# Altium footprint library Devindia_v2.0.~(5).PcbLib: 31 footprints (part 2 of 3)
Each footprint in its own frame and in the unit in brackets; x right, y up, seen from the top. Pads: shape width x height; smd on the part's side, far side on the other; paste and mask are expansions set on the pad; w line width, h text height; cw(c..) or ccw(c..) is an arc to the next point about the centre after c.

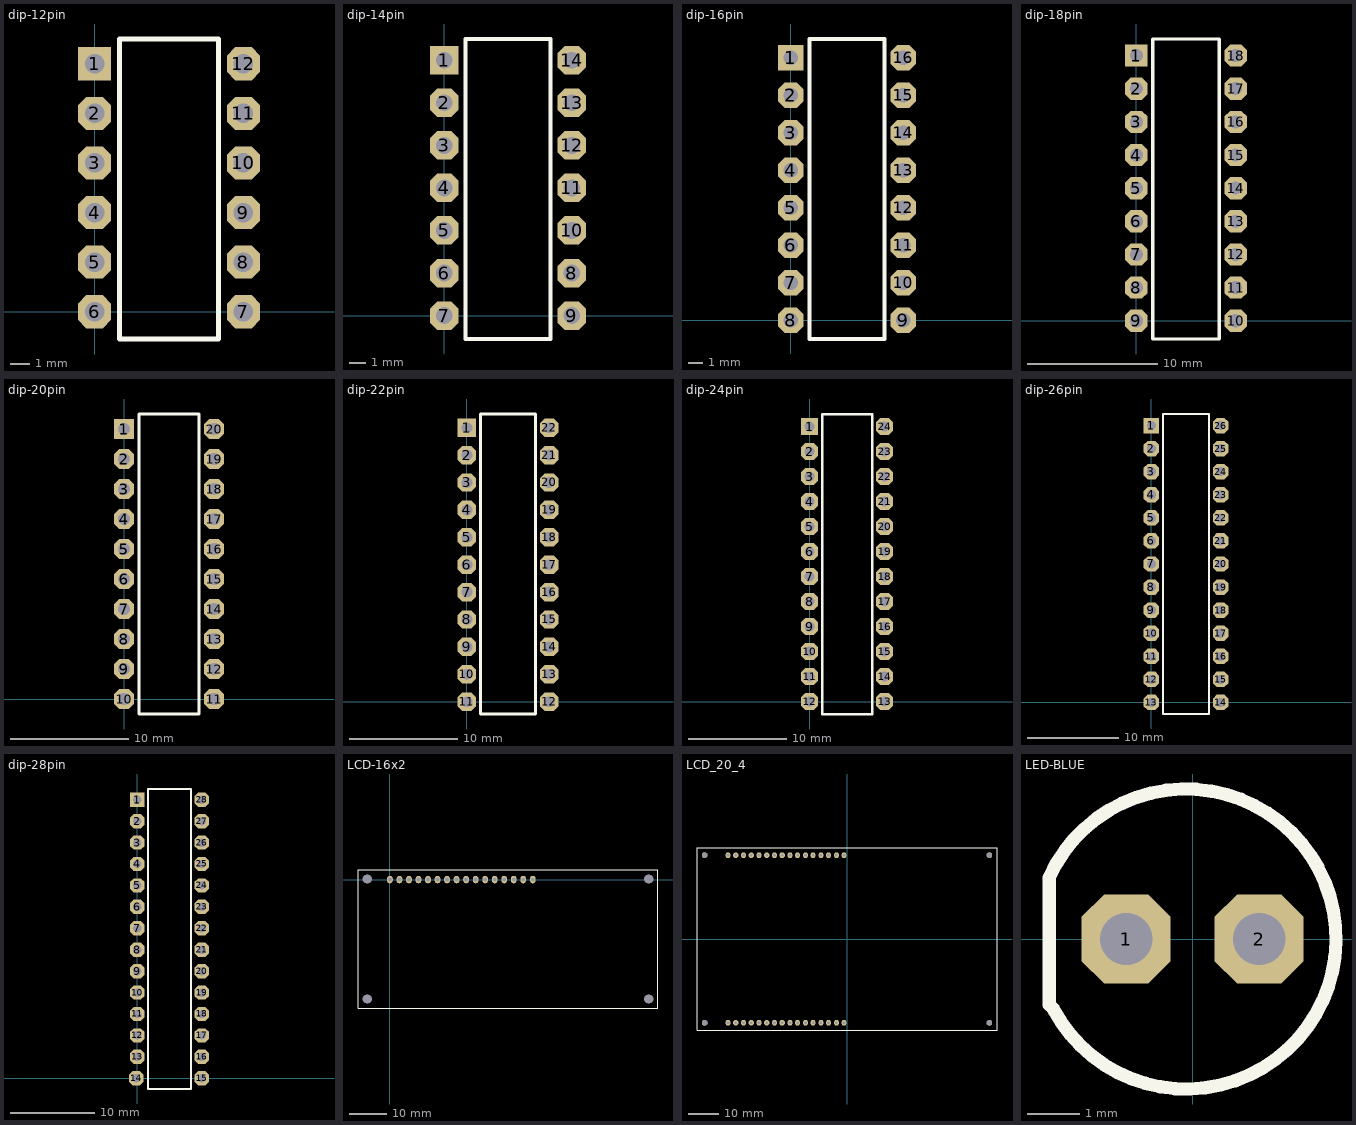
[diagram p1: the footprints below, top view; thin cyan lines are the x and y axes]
## dip-12pin [mm]
pads (12):
  rect 1.7x1.7 hole 1: 1(0,12.7)
  oct 1.7x1.7 hole 1: 2(0,10.16) 3(0,7.62) 4(0,5.08) 5(0,2.54) 6(0,0) 7(7.62,0) 8(7.62,2.54) 9(7.62,5.08) 10(7.62,7.62) 11(7.62,10.16) 12(7.62,12.7)
Top Overlay:
  lines w0.254: 1.27,-1.397 1.27,13.97 6.35,13.97 6.35,-1.397 1.27,-1.397
3D body: height 1.5, standoff 0, extent 7.493,4.699 7.747,5.461
3D body: height 1.63, standoff 1.37, extent 7.494,4.699 7.746,5.461
3D body: height 1.63, standoff 1.37, extent 5.842,4.699 7.747,5.461
3D body: height 2.5, standoff 2, extent 1.778,-1.27 5.842,13.97
3D body: height 2.51, standoff 2.5, extent 2.041,12.212 3.039,13.208
3D body: height 2, standoff 1.1, extent 1.27,-1.397 6.35,13.97
3D body: height 1.5, standoff 0, extent 7.493,12.319 7.747,13.081
3D body: height 1.63, standoff 1.37, extent 7.494,12.319 7.746,13.081
3D body: height 1.5, standoff 0, extent 7.493,9.779 7.747,10.541
3D body: height 1.63, standoff 1.37, extent 7.494,9.779 7.746,10.541
3D body: height 1.5, standoff 0, extent 7.493,7.239 7.747,8.001
3D body: height 1.63, standoff 1.37, extent 7.494,7.239 7.746,8.001
3D body: height 1.5, standoff 0, extent 7.493,2.159 7.747,2.921
3D body: height 1.63, standoff 1.37, extent 7.494,2.159 7.746,2.921
3D body: height 1.5, standoff 0, extent 7.493,-0.381 7.747,0.381
3D body: height 1.63, standoff 1.37, extent 7.494,-0.381 7.746,0.381
3D body: height 1.5, standoff 0, extent -0.127,-0.381 0.127,0.381
3D body: height 1.63, standoff 1.37, extent -0.126,-0.381 0.126,0.381
3D body: height 1.5, standoff 0, extent -0.127,2.159 0.127,2.921
3D body: height 1.63, standoff 1.37, extent -0.126,2.159 0.126,2.921
3D body: height 1.5, standoff 0, extent -0.127,4.699 0.127,5.461
3D body: height 1.63, standoff 1.37, extent -0.126,4.699 0.126,5.461
3D body: height 1.5, standoff 0, extent -0.127,7.239 0.127,8.001
3D body: height 1.63, standoff 1.37, extent -0.126,7.239 0.126,8.001
3D body: height 1.5, standoff 0, extent -0.127,9.779 0.127,10.541
3D body: height 1.63, standoff 1.37, extent -0.126,9.779 0.126,10.541
3D body: height 1.5, standoff 0, extent -0.127,12.319 0.127,13.081
3D body: height 1.63, standoff 1.37, extent -0.126,12.319 0.126,13.081
3D body: height 1.63, standoff 1.37, extent 5.842,12.319 7.747,13.081
3D body: height 1.63, standoff 1.37, extent 5.842,9.779 7.747,10.541
3D body: height 1.63, standoff 1.37, extent 5.842,7.239 7.747,8.001
3D body: height 1.63, standoff 1.37, extent 5.842,2.159 7.747,2.921
3D body: height 1.63, standoff 1.37, extent 5.842,-0.381 7.747,0.381
3D body: height 1.63, standoff 1.37, extent -0.127,-0.381 1.778,0.381
3D body: height 1.63, standoff 1.37, extent -0.127,2.159 1.778,2.921
3D body: height 1.63, standoff 1.37, extent -0.127,4.699 1.778,5.461
3D body: height 1.63, standoff 1.37, extent -0.127,7.239 1.778,8.001
3D body: height 1.63, standoff 1.37, extent -0.127,12.319 1.778,13.081
3D body: height 1.63, standoff 1.37, extent -0.127,9.779 1.778,10.541

## dip-14pin [mm]
pads (14):
  rect 1.7x1.7 hole 1: 1(0,15.24)
  oct 1.7x1.7 hole 1: 2(0,12.7) 3(0,10.16) 4(0,7.62) 5(0,5.08) 6(0,2.54) 7(0,0) 8(7.62,2.54) 9(7.62,0) 10(7.62,5.08) 11(7.62,7.62) 12(7.62,10.16) 13(7.62,12.7) 14(7.62,15.24)
Top Overlay:
  lines w0.254: 1.27,-1.397 6.35,-1.397 6.35,16.51 1.27,16.51 1.27,-1.397
3D body: height 1.5, standoff 0, extent 7.493,2.159 7.747,2.921
3D body: height 1.63, standoff 1.37, extent 7.494,2.159 7.746,2.921
3D body: height 1.63, standoff 1.37, extent 5.842,2.159 7.747,2.921
3D body: height 1.63, standoff 1.37, extent 7.621,14.859 7.873,15.621
3D body: height 1.5, standoff 0, extent 7.62,14.859 7.874,15.621
3D body: height 1.63, standoff 1.37, extent 5.842,14.859 7.747,15.621
3D body: height 1.63, standoff 1.37, extent 5.842,12.319 7.747,13.081
3D body: height 1.5, standoff 0, extent 7.62,12.319 7.874,13.081
3D body: height 1.63, standoff 1.37, extent 7.621,12.319 7.873,13.081
3D body: height 1.63, standoff 1.37, extent -0.127,12.319 1.778,13.081
3D body: height 1.63, standoff 1.37, extent -0.127,14.859 1.778,15.621
3D body: height 1.63, standoff 1.37, extent -0.127,9.779 1.778,10.541
3D body: height 1.63, standoff 1.37, extent -0.127,7.239 1.778,8.001
3D body: height 1.63, standoff 1.37, extent -0.127,4.699 1.778,5.461
3D body: height 1.63, standoff 1.37, extent -0.127,2.159 1.778,2.921
3D body: height 1.63, standoff 1.37, extent -0.127,-0.381 1.778,0.381
3D body: height 1.63, standoff 1.37, extent 5.842,-0.381 7.747,0.381
3D body: height 1.63, standoff 1.37, extent 5.842,4.699 7.747,5.461
3D body: height 1.63, standoff 1.37, extent 5.842,7.239 7.747,8.001
3D body: height 1.63, standoff 1.37, extent 5.842,9.779 7.747,10.541
3D body: height 1.63, standoff 1.37, extent -0.126,14.859 0.126,15.621
3D body: height 1.5, standoff 0, extent -0.127,14.859 0.127,15.621
3D body: height 1.63, standoff 1.37, extent -0.126,12.319 0.126,13.081
3D body: height 1.5, standoff 0, extent -0.127,12.319 0.127,13.081
3D body: height 1.63, standoff 1.37, extent -0.126,9.779 0.126,10.541
3D body: height 1.5, standoff 0, extent -0.127,9.779 0.127,10.541
3D body: height 1.63, standoff 1.37, extent -0.126,7.239 0.126,8.001
3D body: height 1.5, standoff 0, extent -0.127,7.239 0.127,8.001
3D body: height 1.63, standoff 1.37, extent -0.126,4.699 0.126,5.461
3D body: height 1.5, standoff 0, extent -0.127,4.699 0.127,5.461
3D body: height 1.63, standoff 1.37, extent -0.126,2.159 0.126,2.921
3D body: height 1.5, standoff 0, extent -0.127,2.159 0.127,2.921
3D body: height 1.63, standoff 1.37, extent -0.126,-0.381 0.126,0.381
3D body: height 1.5, standoff 0, extent -0.127,-0.381 0.127,0.381
3D body: height 1.63, standoff 1.37, extent 7.494,-0.381 7.746,0.381
3D body: height 1.5, standoff 0, extent 7.493,-0.381 7.747,0.381
3D body: height 1.63, standoff 1.37, extent 7.494,4.699 7.746,5.461
3D body: height 1.5, standoff 0, extent 7.493,4.699 7.747,5.461
3D body: height 1.63, standoff 1.37, extent 7.494,7.239 7.746,8.001
3D body: height 1.5, standoff 0, extent 7.493,7.239 7.747,8.001
3D body: height 1.63, standoff 1.37, extent 7.494,9.779 7.746,10.541
3D body: height 1.5, standoff 0, extent 7.493,9.779 7.747,10.541
3D body: height 2, standoff 1.1, extent 1.27,-1.27 6.35,16.51
3D body: height 2.51, standoff 2.5, extent 2.041,14.752 3.039,15.748
3D body: height 2.5, standoff 2, extent 1.778,-1.397 5.842,16.51

## dip-16pin [mm]
pads (16):
  rect 1.7x1.7 hole 1: 1(0,17.78)
  oct 1.7x1.7 hole 1: 2(0,15.24) 3(0,12.7) 4(0,10.16) 5(0,7.62) 6(0,5.08) 7(0,2.54) 8(0,0) 9(7.62,0) 10(7.62,2.54) 11(7.62,5.08) 12(7.62,7.62) 13(7.62,10.16) 14(7.62,12.7) 15(7.62,15.24) 16(7.62,17.78)
Top Overlay:
  lines w0.254: 1.27,-1.27 1.27,19.05 6.35,19.05 6.35,-1.27 1.27,-1.27
3D body: height 1.63, standoff 1.37, extent 7.621,12.319 7.873,13.081
3D body: height 1.5, standoff 0, extent 7.62,12.319 7.874,13.081
3D body: height 1.63, standoff 1.37, extent 5.842,12.319 7.747,13.081
3D body: height 2.5, standoff 2, extent 1.778,-1.27 5.842,19.05
3D body: height 2.51, standoff 2.5, extent 2.041,17.292 3.039,18.288
3D body: height 1.5, standoff 0, extent 7.493,17.399 7.747,18.161
3D body: height 1.63, standoff 1.37, extent 7.494,17.399 7.746,18.161
3D body: height 2, standoff 1.1, extent 1.27,-1.27 6.35,19.05
3D body: height 1.5, standoff 0, extent 7.493,7.239 7.747,8.001
3D body: height 1.63, standoff 1.37, extent 7.494,7.239 7.746,8.001
3D body: height 1.5, standoff 0, extent 7.493,4.699 7.747,5.461
3D body: height 1.63, standoff 1.37, extent 7.494,4.699 7.746,5.461
3D body: height 1.5, standoff 0, extent 7.493,2.159 7.747,2.921
3D body: height 1.63, standoff 1.37, extent 7.494,2.159 7.746,2.921
3D body: height 1.5, standoff 0, extent 7.493,-0.381 7.747,0.381
3D body: height 1.63, standoff 1.37, extent 7.494,-0.381 7.746,0.381
3D body: height 1.5, standoff 0, extent -0.127,-0.381 0.127,0.381
3D body: height 1.63, standoff 1.37, extent -0.126,-0.381 0.126,0.381
3D body: height 1.5, standoff 0, extent -0.127,2.159 0.127,2.921
3D body: height 1.63, standoff 1.37, extent -0.126,2.159 0.126,2.921
3D body: height 1.5, standoff 0, extent -0.127,4.699 0.127,5.461
3D body: height 1.63, standoff 1.37, extent -0.126,4.699 0.126,5.461
3D body: height 1.5, standoff 0, extent -0.127,7.239 0.127,8.001
3D body: height 1.63, standoff 1.37, extent -0.126,7.239 0.126,8.001
3D body: height 1.5, standoff 0, extent -0.127,9.779 0.127,10.541
3D body: height 1.63, standoff 1.37, extent -0.126,9.779 0.126,10.541
3D body: height 1.5, standoff 0, extent -0.127,12.319 0.127,13.081
3D body: height 1.63, standoff 1.37, extent -0.126,12.319 0.126,13.081
3D body: height 1.5, standoff 0, extent -0.127,14.859 0.127,15.621
3D body: height 1.63, standoff 1.37, extent -0.126,14.859 0.126,15.621
3D body: height 1.5, standoff 0, extent -0.127,17.399 0.127,18.161
3D body: height 1.63, standoff 1.37, extent -0.126,17.399 0.126,18.161
3D body: height 1.63, standoff 1.37, extent 5.842,7.239 7.747,8.001
3D body: height 1.63, standoff 1.37, extent 5.842,4.699 7.747,5.461
3D body: height 1.63, standoff 1.37, extent 5.842,2.159 7.747,2.921
3D body: height 1.63, standoff 1.37, extent 5.842,-0.381 7.747,0.381
3D body: height 1.63, standoff 1.37, extent -0.127,-0.381 1.778,0.381
3D body: height 1.63, standoff 1.37, extent -0.127,2.159 1.778,2.921
3D body: height 1.63, standoff 1.37, extent -0.127,4.699 1.778,5.461
3D body: height 1.63, standoff 1.37, extent -0.127,7.239 1.778,8.001
3D body: height 1.63, standoff 1.37, extent -0.127,9.779 1.778,10.541
3D body: height 1.63, standoff 1.37, extent -0.127,12.319 1.778,13.081
3D body: height 1.63, standoff 1.37, extent -0.127,17.399 1.778,18.161
3D body: height 1.63, standoff 1.37, extent -0.127,14.859 1.778,15.621
3D body: height 1.63, standoff 1.37, extent 7.621,9.779 7.873,10.541
3D body: height 1.5, standoff 0, extent 7.62,9.779 7.874,10.541
3D body: height 1.63, standoff 1.37, extent 5.842,9.779 7.747,10.541
3D body: height 1.63, standoff 1.37, extent 5.842,14.859 7.747,15.621
3D body: height 1.63, standoff 1.37, extent 5.842,17.399 7.747,18.161
3D body: height 1.5, standoff 0, extent 7.62,17.399 7.874,18.161
3D body: height 1.63, standoff 1.37, extent 7.621,17.399 7.873,18.161
3D body: height 1.5, standoff 0, extent 7.62,14.859 7.874,15.621
3D body: height 1.63, standoff 1.37, extent 7.621,14.859 7.873,15.621

## dip-18pin [mm]
pads (18):
  rect 1.7x1.7 hole 1: 1(0,20.32)
  oct 1.7x1.7 hole 1: 2(0,17.78) 3(0,15.24) 4(0,12.7) 5(0,10.16) 6(0,7.62) 7(0,5.08) 8(0,2.54) 9(0,0) 10(7.62,0) 11(7.62,2.54) 12(7.62,5.08) 13(7.62,7.62) 14(7.62,10.16) 15(7.62,12.7) 16(7.62,15.24) 17(7.62,17.78) 18(7.62,20.32)
Top Overlay:
  lines w0.254: 1.27,-1.397 6.35,-1.397 6.35,21.59 1.27,21.59 1.27,-1.397
3D body: height 1.63, standoff 1.37, extent 7.621,12.319 7.873,13.081
3D body: height 1.5, standoff 0, extent 7.62,12.319 7.874,13.081
3D body: height 1.63, standoff 1.37, extent 7.621,14.859 7.873,15.621
3D body: height 1.5, standoff 0, extent 7.62,14.859 7.874,15.621
3D body: height 1.63, standoff 1.37, extent 5.842,19.939 7.747,20.701
3D body: height 1.63, standoff 1.37, extent 5.842,17.399 7.747,18.161
3D body: height 1.63, standoff 1.37, extent 7.621,19.939 7.873,20.701
3D body: height 1.5, standoff 0, extent 7.62,19.939 7.874,20.701
3D body: height 1.63, standoff 1.37, extent 5.842,14.859 7.747,15.621
3D body: height 1.63, standoff 1.37, extent 7.621,17.399 7.873,18.161
3D body: height 1.5, standoff 0, extent 7.62,17.399 7.874,18.161
3D body: height 1.63, standoff 1.37, extent 5.842,12.319 7.747,13.081
3D body: height 1.63, standoff 1.37, extent 5.842,7.239 7.747,8.001
3D body: height 1.5, standoff 0, extent 7.62,7.239 7.874,8.001
3D body: height 1.63, standoff 1.37, extent 7.621,7.239 7.873,8.001
3D body: height 1.63, standoff 1.37, extent -0.127,17.399 1.778,18.161
3D body: height 1.63, standoff 1.37, extent -0.127,19.939 1.778,20.701
3D body: height 1.63, standoff 1.37, extent -0.127,14.859 1.778,15.621
3D body: height 1.63, standoff 1.37, extent -0.127,12.319 1.778,13.081
3D body: height 1.63, standoff 1.37, extent -0.127,9.779 1.778,10.541
3D body: height 1.63, standoff 1.37, extent -0.127,7.239 1.778,8.001
3D body: height 1.63, standoff 1.37, extent -0.127,4.699 1.778,5.461
3D body: height 1.63, standoff 1.37, extent -0.127,2.159 1.778,2.921
3D body: height 1.63, standoff 1.37, extent 5.842,-0.381 7.747,0.381
3D body: height 1.63, standoff 1.37, extent 5.842,2.159 7.747,2.921
3D body: height 1.63, standoff 1.37, extent 5.842,4.699 7.747,5.461
3D body: height 1.63, standoff 1.37, extent -0.126,19.939 0.126,20.701
3D body: height 1.5, standoff 0, extent -0.127,19.939 0.127,20.701
3D body: height 1.63, standoff 1.37, extent -0.126,17.399 0.126,18.161
3D body: height 1.5, standoff 0, extent -0.127,17.399 0.127,18.161
3D body: height 1.63, standoff 1.37, extent -0.126,14.859 0.126,15.621
3D body: height 1.5, standoff 0, extent -0.127,14.859 0.127,15.621
3D body: height 1.63, standoff 1.37, extent -0.126,12.319 0.126,13.081
3D body: height 1.5, standoff 0, extent -0.127,12.319 0.127,13.081
3D body: height 1.63, standoff 1.37, extent -0.126,9.779 0.126,10.541
3D body: height 1.5, standoff 0, extent -0.127,9.779 0.127,10.541
3D body: height 1.63, standoff 1.37, extent -0.126,7.239 0.126,8.001
3D body: height 1.5, standoff 0, extent -0.127,7.239 0.127,8.001
3D body: height 1.63, standoff 1.37, extent -0.126,4.699 0.126,5.461
3D body: height 1.5, standoff 0, extent -0.127,4.699 0.127,5.461
3D body: height 1.63, standoff 1.37, extent -0.126,2.159 0.126,2.921
3D body: height 1.5, standoff 0, extent -0.127,2.159 0.127,2.921
3D body: height 1.63, standoff 1.37, extent 7.494,-0.381 7.746,0.381
3D body: height 1.5, standoff 0, extent 7.493,-0.381 7.747,0.381
3D body: height 1.63, standoff 1.37, extent 7.494,2.159 7.746,2.921
3D body: height 1.5, standoff 0, extent 7.493,2.159 7.747,2.921
3D body: height 1.63, standoff 1.37, extent 7.494,4.699 7.746,5.461
3D body: height 1.5, standoff 0, extent 7.493,4.699 7.747,5.461
3D body: height 2, standoff 1.1, extent 1.27,-1.397 6.35,21.59
3D body: height 1.63, standoff 1.37, extent 7.494,14.859 7.746,15.621
3D body: height 1.5, standoff 0, extent 7.493,14.859 7.747,15.621
3D body: height 2.51, standoff 2.5, extent 2.041,19.832 3.039,20.828
3D body: height 2.5, standoff 2, extent 1.778,-1.397 5.842,21.59
3D body: height 1.63, standoff 1.37, extent -0.127,-0.381 1.778,0.381
3D body: height 1.63, standoff 1.37, extent -0.126,-0.381 0.126,0.381
3D body: height 1.5, standoff 0, extent -0.127,-0.381 0.127,0.381
3D body: height 1.63, standoff 1.37, extent 5.842,9.779 7.747,10.541
3D body: height 1.63, standoff 1.37, extent 7.494,9.779 7.746,10.541
3D body: height 1.5, standoff 0, extent 7.493,9.779 7.747,10.541

## dip-20pin [mm]
pads (20):
  rect 1.7x1.7 hole 1: 1(0,22.86)
  oct 1.7x1.7 hole 1: 2(0,20.32) 3(0,17.78) 4(0,15.24) 5(0,12.7) 6(0,10.16) 7(0,7.62) 8(0,5.08) 9(0,2.54) 10(0,0) 11(7.62,0) 12(7.62,2.54) 13(7.62,5.08) 14(7.62,7.62) 15(7.62,10.16) 16(7.62,12.7) 17(7.62,15.24) 18(7.62,17.78) 19(7.62,20.32) 20(7.62,22.86)
Top Overlay:
  lines w0.254: 1.27,-1.27 6.35,-1.27 6.35,24.13 1.27,24.13 1.27,-1.27
3D body: height 1.5, standoff 0, extent -0.127,4.699 0.127,5.461
3D body: height 1.63, standoff 1.37, extent -0.126,4.699 0.126,5.461
3D body: height 1.63, standoff 1.37, extent -0.127,4.699 1.778,5.461
3D body: height 1.5, standoff 0, extent 7.493,7.239 7.747,8.001
3D body: height 1.63, standoff 1.37, extent 7.494,7.239 7.746,8.001
3D body: height 1.63, standoff 1.37, extent 5.842,7.239 7.747,8.001
3D body: height 1.5, standoff 0, extent -0.127,2.159 0.127,2.921
3D body: height 1.63, standoff 1.37, extent -0.126,2.159 0.126,2.921
3D body: height 1.63, standoff 1.37, extent -0.127,2.159 1.778,2.921
3D body: height 1.63, standoff 1.37, extent 7.621,9.779 7.873,10.541
3D body: height 1.5, standoff 0, extent 7.62,9.779 7.874,10.541
3D body: height 1.63, standoff 1.37, extent 7.621,12.319 7.873,13.081
3D body: height 1.5, standoff 0, extent 7.62,12.319 7.874,13.081
3D body: height 1.63, standoff 1.37, extent 7.621,22.479 7.873,23.241
3D body: height 1.5, standoff 0, extent 7.62,22.479 7.874,23.241
3D body: height 1.63, standoff 1.37, extent 5.842,17.399 7.747,18.161
3D body: height 1.63, standoff 1.37, extent 7.621,19.939 7.873,20.701
3D body: height 1.5, standoff 0, extent 7.62,19.939 7.874,20.701
3D body: height 1.63, standoff 1.37, extent 5.842,14.859 7.747,15.621
3D body: height 1.63, standoff 1.37, extent 7.621,17.399 7.873,18.161
3D body: height 1.5, standoff 0, extent 7.62,17.399 7.874,18.161
3D body: height 1.63, standoff 1.37, extent 5.842,12.319 7.747,13.081
3D body: height 1.63, standoff 1.37, extent 7.621,14.859 7.873,15.621
3D body: height 1.5, standoff 0, extent 7.62,14.859 7.874,15.621
3D body: height 1.63, standoff 1.37, extent 5.842,9.779 7.747,10.541
3D body: height 1.63, standoff 1.37, extent 5.842,19.939 7.747,20.701
3D body: height 1.63, standoff 1.37, extent 5.842,22.479 7.747,23.241
3D body: height 1.63, standoff 1.37, extent 5.842,4.699 7.747,5.461
3D body: height 1.5, standoff 0, extent 7.62,4.699 7.874,5.461
3D body: height 1.63, standoff 1.37, extent 7.621,4.699 7.873,5.461
3D body: height 1.63, standoff 1.37, extent -0.127,19.939 1.778,20.701
3D body: height 1.63, standoff 1.37, extent -0.127,22.479 1.778,23.241
3D body: height 1.63, standoff 1.37, extent -0.127,17.399 1.778,18.161
3D body: height 1.63, standoff 1.37, extent -0.127,14.859 1.778,15.621
3D body: height 1.63, standoff 1.37, extent -0.127,12.319 1.778,13.081
3D body: height 1.63, standoff 1.37, extent -0.127,9.779 1.778,10.541
3D body: height 1.63, standoff 1.37, extent -0.127,7.239 1.778,8.001
3D body: height 1.63, standoff 1.37, extent -0.127,-0.381 1.778,0.381
3D body: height 1.63, standoff 1.37, extent 5.842,-0.381 7.747,0.381
3D body: height 1.63, standoff 1.37, extent 5.842,2.159 7.747,2.921
3D body: height 1.63, standoff 1.37, extent -0.126,22.479 0.126,23.241
3D body: height 1.5, standoff 0, extent -0.127,22.479 0.127,23.241
3D body: height 1.63, standoff 1.37, extent -0.126,19.939 0.126,20.701
3D body: height 1.5, standoff 0, extent -0.127,19.939 0.127,20.701
3D body: height 1.63, standoff 1.37, extent -0.126,17.399 0.126,18.161
3D body: height 1.5, standoff 0, extent -0.127,17.399 0.127,18.161
3D body: height 1.63, standoff 1.37, extent -0.126,14.859 0.126,15.621
3D body: height 1.5, standoff 0, extent -0.127,14.859 0.127,15.621
3D body: height 1.63, standoff 1.37, extent -0.126,12.319 0.126,13.081
3D body: height 1.5, standoff 0, extent -0.127,12.319 0.127,13.081
3D body: height 1.63, standoff 1.37, extent -0.126,9.779 0.126,10.541
3D body: height 1.5, standoff 0, extent -0.127,9.779 0.127,10.541
3D body: height 1.63, standoff 1.37, extent -0.126,7.239 0.126,8.001
3D body: height 1.5, standoff 0, extent -0.127,7.239 0.127,8.001
3D body: height 1.63, standoff 1.37, extent -0.126,-0.381 0.126,0.381
3D body: height 1.5, standoff 0, extent -0.127,-0.381 0.127,0.381
3D body: height 1.63, standoff 1.37, extent 7.494,-0.381 7.746,0.381
3D body: height 1.5, standoff 0, extent 7.493,-0.381 7.747,0.381
3D body: height 1.63, standoff 1.37, extent 7.494,2.159 7.746,2.921
3D body: height 1.5, standoff 0, extent 7.493,2.159 7.747,2.921
3D body: height 2, standoff 1.1, extent 1.27,-1.27 6.35,24.13
3D body: height 1.63, standoff 1.37, extent 7.494,12.319 7.746,13.081
3D body: height 1.5, standoff 0, extent 7.493,12.319 7.747,13.081
3D body: height 2.51, standoff 2.5, extent 2.041,22.372 3.039,23.368
3D body: height 2.5, standoff 2, extent 1.778,-1.27 5.842,24.13

## dip-22pin [mm]
pads (22):
  rect 1.7x1.7 hole 1: 1(0,25.4)
  oct 1.7x1.7 hole 1: 2(0,22.86) 3(0,20.32) 4(0,17.78) 5(0,15.24) 6(0,12.7) 7(0,10.16) 8(0,7.62) 9(0,5.08) 10(0,2.54) 11(0,0) 12(7.62,0) 13(7.62,2.54) 14(7.62,5.08) 15(7.62,7.62) 16(7.62,10.16) 17(7.62,12.7) 18(7.62,15.24) 19(7.62,17.78) 20(7.62,20.32) 21(7.62,22.86) 22(7.62,25.4)
Top Overlay:
  lines w0.254: 1.27,-1.143 1.27,26.67 6.35,26.67 6.35,-1.143 1.27,-1.143
3D body: height 2.5, standoff 2, extent 1.778,-1.143 5.842,26.67
3D body: height 2.51, standoff 2.5, extent 2.041,24.912 3.039,25.908
3D body: height 1.5, standoff 0, extent 7.493,9.779 7.747,10.541
3D body: height 1.63, standoff 1.37, extent 7.494,9.779 7.746,10.541
3D body: height 2, standoff 1.1, extent 1.27,-1.143 6.35,26.67
3D body: height 1.5, standoff 0, extent 7.493,-0.381 7.747,0.381
3D body: height 1.63, standoff 1.37, extent 7.494,-0.381 7.746,0.381
3D body: height 1.5, standoff 0, extent -0.127,-0.381 0.127,0.381
3D body: height 1.63, standoff 1.37, extent -0.126,-0.381 0.126,0.381
3D body: height 1.5, standoff 0, extent -0.127,2.159 0.127,2.921
3D body: height 1.63, standoff 1.37, extent -0.126,2.159 0.126,2.921
3D body: height 1.5, standoff 0, extent -0.127,7.239 0.127,8.001
3D body: height 1.63, standoff 1.37, extent -0.126,7.239 0.126,8.001
3D body: height 1.5, standoff 0, extent -0.127,9.779 0.127,10.541
3D body: height 1.63, standoff 1.37, extent -0.126,9.779 0.126,10.541
3D body: height 1.5, standoff 0, extent -0.127,12.319 0.127,13.081
3D body: height 1.63, standoff 1.37, extent -0.126,12.319 0.126,13.081
3D body: height 1.5, standoff 0, extent -0.127,14.859 0.127,15.621
3D body: height 1.63, standoff 1.37, extent -0.126,14.859 0.126,15.621
3D body: height 1.5, standoff 0, extent -0.127,17.399 0.127,18.161
3D body: height 1.63, standoff 1.37, extent -0.126,17.399 0.126,18.161
3D body: height 1.5, standoff 0, extent -0.127,19.939 0.127,20.701
3D body: height 1.63, standoff 1.37, extent -0.126,19.939 0.126,20.701
3D body: height 1.5, standoff 0, extent -0.127,22.479 0.127,23.241
3D body: height 1.63, standoff 1.37, extent -0.126,22.479 0.126,23.241
3D body: height 1.5, standoff 0, extent -0.127,25.019 0.127,25.781
3D body: height 1.63, standoff 1.37, extent -0.126,25.019 0.126,25.781
3D body: height 1.63, standoff 1.37, extent 5.842,-0.381 7.747,0.381
3D body: height 1.63, standoff 1.37, extent -0.127,-0.381 1.778,0.381
3D body: height 1.63, standoff 1.37, extent -0.127,2.159 1.778,2.921
3D body: height 1.63, standoff 1.37, extent -0.127,7.239 1.778,8.001
3D body: height 1.63, standoff 1.37, extent -0.127,9.779 1.778,10.541
3D body: height 1.63, standoff 1.37, extent -0.127,12.319 1.778,13.081
3D body: height 1.63, standoff 1.37, extent -0.127,14.859 1.778,15.621
3D body: height 1.63, standoff 1.37, extent -0.127,17.399 1.778,18.161
3D body: height 1.63, standoff 1.37, extent -0.127,19.939 1.778,20.701
3D body: height 1.63, standoff 1.37, extent -0.127,25.019 1.778,25.781
3D body: height 1.63, standoff 1.37, extent -0.127,22.479 1.778,23.241
3D body: height 1.63, standoff 1.37, extent 7.621,2.159 7.873,2.921
3D body: height 1.5, standoff 0, extent 7.62,2.159 7.874,2.921
3D body: height 1.63, standoff 1.37, extent 5.842,2.159 7.747,2.921
3D body: height 1.63, standoff 1.37, extent 5.842,25.019 7.747,25.781
3D body: height 1.63, standoff 1.37, extent 5.842,22.479 7.747,23.241
3D body: height 1.63, standoff 1.37, extent 5.842,19.939 7.747,20.701
3D body: height 1.5, standoff 0, extent 7.62,25.019 7.874,25.781
3D body: height 1.63, standoff 1.37, extent 7.621,25.019 7.873,25.781
3D body: height 1.63, standoff 1.37, extent 5.842,17.399 7.747,18.161
3D body: height 1.5, standoff 0, extent 7.62,22.479 7.874,23.241
3D body: height 1.63, standoff 1.37, extent 7.621,22.479 7.873,23.241
3D body: height 1.63, standoff 1.37, extent 5.842,7.239 7.747,8.001
3D body: height 1.5, standoff 0, extent 7.62,12.319 7.874,13.081
3D body: height 1.63, standoff 1.37, extent 7.621,12.319 7.873,13.081
3D body: height 1.63, standoff 1.37, extent 5.842,9.779 7.747,10.541
3D body: height 1.5, standoff 0, extent 7.62,14.859 7.874,15.621
3D body: height 1.63, standoff 1.37, extent 7.621,14.859 7.873,15.621
3D body: height 1.63, standoff 1.37, extent 5.842,12.319 7.747,13.081
3D body: height 1.5, standoff 0, extent 7.62,17.399 7.874,18.161
3D body: height 1.63, standoff 1.37, extent 7.621,17.399 7.873,18.161
3D body: height 1.63, standoff 1.37, extent 5.842,14.859 7.747,15.621
3D body: height 1.5, standoff 0, extent 7.62,19.939 7.874,20.701
3D body: height 1.63, standoff 1.37, extent 7.621,19.939 7.873,20.701
3D body: height 1.5, standoff 0, extent 7.62,9.779 7.874,10.541
3D body: height 1.63, standoff 1.37, extent 7.621,9.779 7.873,10.541
3D body: height 1.5, standoff 0, extent 7.62,7.239 7.874,8.001
3D body: height 1.63, standoff 1.37, extent 7.621,7.239 7.873,8.001
3D body: height 1.63, standoff 1.37, extent -0.127,4.699 1.778,5.461
3D body: height 1.63, standoff 1.37, extent -0.126,4.699 0.126,5.461
3D body: height 1.5, standoff 0, extent -0.127,4.699 0.127,5.461
3D body: height 1.63, standoff 1.37, extent 5.842,4.699 7.747,5.461
3D body: height 1.63, standoff 1.37, extent 7.494,4.699 7.746,5.461
3D body: height 1.5, standoff 0, extent 7.493,4.699 7.747,5.461

## dip-24pin [mm]
pads (24):
  rect 1.7x1.7 hole 1: 1(0,27.94)
  oct 1.7x1.7 hole 1: 2(0,25.4) 3(0,22.86) 4(0,20.32) 5(0,17.78) 6(0,15.24) 7(0,12.7) 8(0,10.16) 9(0,7.62) 10(0,5.08) 11(0,2.54) 12(0,0) 13(7.62,0) 14(7.62,2.54) 15(7.62,5.08) 16(7.62,7.62) 17(7.62,10.16) 18(7.62,12.7) 19(7.62,15.24) 20(7.62,17.78) 21(7.62,20.32) 22(7.62,22.86) 23(7.62,25.4) 24(7.62,27.94)
Top Overlay:
  lines w0.254: 1.27,-1.27 6.35,-1.27 6.35,29.21 1.27,29.21 1.27,-1.27
3D body: height 1.63, standoff 1.37, extent 7.621,4.699 7.873,5.461
3D body: height 1.5, standoff 0, extent 7.62,4.699 7.874,5.461
3D body: height 1.63, standoff 1.37, extent 7.621,7.239 7.873,8.001
3D body: height 1.5, standoff 0, extent 7.62,7.239 7.874,8.001
3D body: height 1.63, standoff 1.37, extent 5.842,2.159 7.747,2.921
3D body: height 1.63, standoff 1.37, extent 7.621,17.399 7.873,18.161
3D body: height 1.5, standoff 0, extent 7.62,17.399 7.874,18.161
3D body: height 1.63, standoff 1.37, extent 5.842,12.319 7.747,13.081
3D body: height 1.63, standoff 1.37, extent 7.621,14.859 7.873,15.621
3D body: height 1.5, standoff 0, extent 7.62,14.859 7.874,15.621
3D body: height 1.63, standoff 1.37, extent 5.842,9.779 7.747,10.541
3D body: height 1.63, standoff 1.37, extent 7.621,12.319 7.873,13.081
3D body: height 1.5, standoff 0, extent 7.62,12.319 7.874,13.081
3D body: height 1.63, standoff 1.37, extent 5.842,7.239 7.747,8.001
3D body: height 1.63, standoff 1.37, extent 7.621,9.779 7.873,10.541
3D body: height 1.5, standoff 0, extent 7.62,9.779 7.874,10.541
3D body: height 1.63, standoff 1.37, extent 5.842,4.699 7.747,5.461
3D body: height 1.63, standoff 1.37, extent 7.621,19.939 7.873,20.701
3D body: height 1.5, standoff 0, extent 7.62,19.939 7.874,20.701
3D body: height 1.63, standoff 1.37, extent 5.842,14.859 7.747,15.621
3D body: height 1.63, standoff 1.37, extent 7.621,22.479 7.873,23.241
3D body: height 1.5, standoff 0, extent 7.62,22.479 7.874,23.241
3D body: height 1.63, standoff 1.37, extent 5.842,17.399 7.747,18.161
3D body: height 1.63, standoff 1.37, extent 7.621,25.019 7.873,25.781
3D body: height 1.5, standoff 0, extent 7.62,25.019 7.874,25.781
3D body: height 1.63, standoff 1.37, extent 5.842,19.939 7.747,20.701
3D body: height 1.63, standoff 1.37, extent 7.621,27.559 7.873,28.321
3D body: height 1.5, standoff 0, extent 7.62,27.559 7.874,28.321
3D body: height 1.63, standoff 1.37, extent 5.842,22.479 7.747,23.241
3D body: height 1.63, standoff 1.37, extent 5.842,25.019 7.747,25.781
3D body: height 1.63, standoff 1.37, extent 5.842,27.559 7.747,28.321
3D body: height 1.63, standoff 1.37, extent 5.842,-0.381 7.747,0.381
3D body: height 1.5, standoff 0, extent 7.62,-0.381 7.874,0.381
3D body: height 1.63, standoff 1.37, extent 7.621,-0.381 7.873,0.381
3D body: height 1.63, standoff 1.37, extent -0.127,25.019 1.778,25.781
3D body: height 1.63, standoff 1.37, extent -0.127,27.559 1.778,28.321
3D body: height 1.63, standoff 1.37, extent -0.127,22.479 1.778,23.241
3D body: height 1.63, standoff 1.37, extent -0.127,19.939 1.778,20.701
3D body: height 1.63, standoff 1.37, extent -0.127,17.399 1.778,18.161
3D body: height 1.63, standoff 1.37, extent -0.127,14.859 1.778,15.621
3D body: height 1.63, standoff 1.37, extent -0.127,12.319 1.778,13.081
3D body: height 1.63, standoff 1.37, extent -0.127,9.779 1.778,10.541
3D body: height 1.63, standoff 1.37, extent -0.127,7.239 1.778,8.001
3D body: height 1.63, standoff 1.37, extent -0.127,4.699 1.778,5.461
3D body: height 1.63, standoff 1.37, extent -0.127,2.159 1.778,2.921
3D body: height 1.63, standoff 1.37, extent -0.127,-0.381 1.778,0.381
3D body: height 1.63, standoff 1.37, extent -0.126,27.559 0.126,28.321
3D body: height 1.5, standoff 0, extent -0.127,27.559 0.127,28.321
3D body: height 1.63, standoff 1.37, extent -0.126,25.019 0.126,25.781
3D body: height 1.5, standoff 0, extent -0.127,25.019 0.127,25.781
3D body: height 1.63, standoff 1.37, extent -0.126,22.479 0.126,23.241
3D body: height 1.5, standoff 0, extent -0.127,22.479 0.127,23.241
3D body: height 1.63, standoff 1.37, extent -0.126,19.939 0.126,20.701
3D body: height 1.5, standoff 0, extent -0.127,19.939 0.127,20.701
3D body: height 1.63, standoff 1.37, extent -0.126,17.399 0.126,18.161
3D body: height 1.5, standoff 0, extent -0.127,17.399 0.127,18.161
3D body: height 1.63, standoff 1.37, extent -0.126,14.859 0.126,15.621
3D body: height 1.5, standoff 0, extent -0.127,14.859 0.127,15.621
3D body: height 1.63, standoff 1.37, extent -0.126,12.319 0.126,13.081
3D body: height 1.5, standoff 0, extent -0.127,12.319 0.127,13.081
3D body: height 1.63, standoff 1.37, extent -0.126,9.779 0.126,10.541
3D body: height 1.5, standoff 0, extent -0.127,9.779 0.127,10.541
3D body: height 1.63, standoff 1.37, extent -0.126,7.112 0.126,7.874
3D body: height 1.5, standoff 0, extent -0.127,7.112 0.127,7.874
3D body: height 1.63, standoff 1.37, extent -0.126,4.699 0.126,5.461
3D body: height 1.5, standoff 0, extent -0.127,4.699 0.127,5.461
3D body: height 1.63, standoff 1.37, extent -0.126,2.159 0.126,2.921
3D body: height 1.5, standoff 0, extent -0.127,2.159 0.127,2.921
3D body: height 1.63, standoff 1.37, extent -0.126,-0.381 0.126,0.381
3D body: height 1.5, standoff 0, extent -0.127,-0.381 0.127,0.381
3D body: height 2, standoff 1.1, extent 1.27,-1.27 6.35,29.21
3D body: height 1.63, standoff 1.37, extent 7.494,7.239 7.746,8.001
3D body: height 1.5, standoff 0, extent 7.493,7.239 7.747,8.001
3D body: height 2.51, standoff 2.5, extent 2.041,27.452 3.039,28.448
3D body: height 2.5, standoff 2, extent 1.778,-1.27 5.842,29.21

## dip-26pin [mm]
pads (26):
  rect 1.7x1.7 hole 1: 1(0,30.48)
  oct 1.7x1.7 hole 1: 2(0,27.94) 3(0,25.4) 4(0,22.86) 5(0,20.32) 6(0,17.78) 7(0,15.24) 8(0,12.7) 9(0,10.16) 10(0,7.62) 11(0,5.08) 12(0,2.54) 13(0,0) 14(7.62,0) 15(7.62,2.54) 16(7.62,5.08) 17(7.62,7.62) 18(7.62,10.16) 19(7.62,12.7) 20(7.62,15.24) 21(7.62,17.78) 22(7.62,20.32) 23(7.62,22.86) 24(7.62,25.4) 25(7.62,27.94) 26(7.62,30.48)
Top Overlay:
  lines w0.254: 1.27,-1.27 6.35,-1.27 6.35,31.75 1.27,31.75 1.27,-1.27
3D body: height 1.63, standoff 1.37, extent 7.621,2.159 7.873,2.921
3D body: height 1.5, standoff 0, extent 7.62,2.159 7.874,2.921
3D body: height 1.63, standoff 1.37, extent 7.621,4.699 7.873,5.461
3D body: height 1.5, standoff 0, extent 7.62,4.699 7.874,5.461
3D body: height 1.63, standoff 1.37, extent 5.842,-0.381 7.747,0.381
3D body: height 1.63, standoff 1.37, extent 7.621,14.859 7.873,15.621
3D body: height 1.5, standoff 0, extent 7.62,14.859 7.874,15.621
3D body: height 1.63, standoff 1.37, extent 5.842,9.779 7.747,10.541
3D body: height 1.63, standoff 1.37, extent 7.621,12.319 7.873,13.081
3D body: height 1.5, standoff 0, extent 7.62,12.319 7.874,13.081
3D body: height 1.63, standoff 1.37, extent 5.842,7.239 7.747,8.001
3D body: height 1.63, standoff 1.37, extent 7.621,9.779 7.873,10.541
3D body: height 1.5, standoff 0, extent 7.62,9.779 7.874,10.541
3D body: height 1.63, standoff 1.37, extent 5.842,4.699 7.747,5.461
3D body: height 1.63, standoff 1.37, extent 7.621,7.239 7.873,8.001
3D body: height 1.5, standoff 0, extent 7.62,7.239 7.874,8.001
3D body: height 1.63, standoff 1.37, extent 5.842,2.159 7.747,2.921
3D body: height 1.63, standoff 1.37, extent 7.621,17.399 7.873,18.161
3D body: height 1.5, standoff 0, extent 7.62,17.399 7.874,18.161
3D body: height 1.63, standoff 1.37, extent 5.842,12.319 7.747,13.081
3D body: height 1.63, standoff 1.37, extent 7.621,19.939 7.873,20.701
3D body: height 1.5, standoff 0, extent 7.62,19.939 7.874,20.701
3D body: height 1.63, standoff 1.37, extent 5.842,14.859 7.747,15.621
3D body: height 1.63, standoff 1.37, extent 7.621,22.479 7.873,23.241
3D body: height 1.5, standoff 0, extent 7.62,22.479 7.874,23.241
3D body: height 1.63, standoff 1.37, extent 5.842,17.399 7.747,18.161
3D body: height 1.63, standoff 1.37, extent 7.621,25.019 7.873,25.781
3D body: height 1.5, standoff 0, extent 7.62,25.019 7.874,25.781
3D body: height 1.63, standoff 1.37, extent 5.842,19.939 7.747,20.701
3D body: height 1.63, standoff 1.37, extent 7.621,27.559 7.873,28.321
3D body: height 1.5, standoff 0, extent 7.62,27.559 7.874,28.321
3D body: height 1.63, standoff 1.37, extent 5.842,22.479 7.747,23.241
3D body: height 1.63, standoff 1.37, extent 7.621,30.099 7.873,30.861
3D body: height 1.5, standoff 0, extent 7.62,30.099 7.874,30.861
3D body: height 1.63, standoff 1.37, extent 5.842,25.019 7.747,25.781
3D body: height 1.63, standoff 1.37, extent 5.842,27.559 7.747,28.321
3D body: height 1.63, standoff 1.37, extent 5.842,30.099 7.747,30.861
3D body: height 1.63, standoff 1.37, extent -0.127,-0.381 1.778,0.381
3D body: height 1.5, standoff 0, extent -0.254,-0.381 0,0.381
3D body: height 1.63, standoff 1.37, extent -0.253,-0.381 -0.001,0.381
3D body: height 1.63, standoff 1.37, extent -0.127,27.559 1.778,28.321
3D body: height 1.63, standoff 1.37, extent -0.127,30.099 1.778,30.861
3D body: height 1.63, standoff 1.37, extent -0.127,25.019 1.778,25.781
3D body: height 1.63, standoff 1.37, extent -0.127,22.479 1.778,23.241
3D body: height 1.63, standoff 1.37, extent -0.127,19.939 1.778,20.701
3D body: height 1.63, standoff 1.37, extent -0.127,17.399 1.778,18.161
3D body: height 1.63, standoff 1.37, extent -0.127,14.859 1.778,15.621
3D body: height 1.63, standoff 1.37, extent -0.127,12.319 1.778,13.081
3D body: height 1.63, standoff 1.37, extent -0.127,9.779 1.778,10.541
3D body: height 1.63, standoff 1.37, extent -0.127,7.239 1.778,8.001
3D body: height 1.63, standoff 1.37, extent -0.127,4.699 1.778,5.461
3D body: height 1.63, standoff 1.37, extent -0.127,2.159 1.778,2.921
3D body: height 1.63, standoff 1.37, extent -0.126,30.099 0.126,30.861
3D body: height 1.5, standoff 0, extent -0.127,30.099 0.127,30.861
3D body: height 1.63, standoff 1.37, extent -0.126,27.559 0.126,28.321
3D body: height 1.5, standoff 0, extent -0.127,27.559 0.127,28.321
3D body: height 1.63, standoff 1.37, extent -0.126,25.019 0.126,25.781
3D body: height 1.5, standoff 0, extent -0.127,25.019 0.127,25.781
3D body: height 1.63, standoff 1.37, extent -0.126,22.479 0.126,23.241
3D body: height 1.5, standoff 0, extent -0.127,22.479 0.127,23.241
3D body: height 1.63, standoff 1.37, extent -0.126,19.939 0.126,20.701
3D body: height 1.5, standoff 0, extent -0.127,19.939 0.127,20.701
3D body: height 1.63, standoff 1.37, extent -0.126,17.399 0.126,18.161
3D body: height 1.5, standoff 0, extent -0.127,17.399 0.127,18.161
3D body: height 1.63, standoff 1.37, extent -0.126,14.859 0.126,15.621
3D body: height 1.5, standoff 0, extent -0.127,14.859 0.127,15.621
3D body: height 1.63, standoff 1.37, extent -0.126,12.319 0.126,13.081
3D body: height 1.5, standoff 0, extent -0.127,12.319 0.127,13.081
3D body: height 1.63, standoff 1.37, extent -0.126,9.652 0.126,10.414
3D body: height 1.5, standoff 0, extent -0.127,9.652 0.127,10.414
3D body: height 1.63, standoff 1.37, extent -0.126,7.239 0.126,8.001
3D body: height 1.5, standoff 0, extent -0.127,7.239 0.127,8.001
3D body: height 1.63, standoff 1.37, extent -0.126,4.699 0.126,5.461
3D body: height 1.5, standoff 0, extent -0.127,4.699 0.127,5.461
3D body: height 1.63, standoff 1.37, extent -0.126,2.159 0.126,2.921
3D body: height 1.5, standoff 0, extent -0.127,2.159 0.127,2.921
3D body: height 2, standoff 1.1, extent 1.27,-1.27 6.35,31.75
3D body: height 1.63, standoff 1.37, extent 7.494,4.699 7.746,5.461
3D body: height 1.5, standoff 0, extent 7.493,4.699 7.747,5.461
3D body: height 2.51, standoff 2.5, extent 2.041,29.992 3.039,30.988
3D body: height 2.5, standoff 2, extent 1.778,-1.27 5.842,31.75

## dip-28pin [mm]
pads (28):
  rect 1.7x1.7 hole 1: 1(0,33.02)
  oct 1.7x1.7 hole 1: 2(0,30.48) 3(0,27.94) 4(0,25.4) 5(0,22.86) 6(0,20.32) 7(0,17.78) 8(0,15.24) 9(0,12.7) 10(0,10.16) 11(0,7.62) 12(0,5.08) 13(0,2.54) 14(-0.126,0) 15(7.62,0) 16(7.62,2.54) 17(7.62,5.08) 18(7.62,7.62) 19(7.62,10.16) 20(7.62,12.7) 21(7.62,15.24) 22(7.62,17.78) 23(7.62,20.32) 24(7.62,22.86) 25(7.62,25.4) 26(7.62,27.94) 27(7.62,30.48) 28(7.62,33.02)
Top Overlay:
  lines w0.254: 1.27,-1.27 6.35,-1.27 6.35,34.29 1.27,34.29 1.27,-1.27
3D body: height 1.63, standoff 1.37, extent 7.621,-0.381 7.873,0.381
3D body: height 1.5, standoff 0, extent 7.62,-0.381 7.874,0.381
3D body: height 1.63, standoff 1.37, extent 5.842,-0.381 7.747,0.381
3D body: height 1.63, standoff 1.37, extent 7.621,2.159 7.873,2.921
3D body: height 1.5, standoff 0, extent 7.62,2.159 7.874,2.921
3D body: height 1.63, standoff 1.37, extent 5.842,2.159 7.747,2.921
3D body: height 1.63, standoff 1.37, extent 7.621,12.319 7.873,13.081
3D body: height 1.5, standoff 0, extent 7.62,12.319 7.874,13.081
3D body: height 1.63, standoff 1.37, extent 5.842,12.319 7.747,13.081
3D body: height 1.63, standoff 1.37, extent 7.621,9.779 7.873,10.541
3D body: height 1.5, standoff 0, extent 7.62,9.779 7.874,10.541
3D body: height 1.63, standoff 1.37, extent 5.842,9.779 7.747,10.541
3D body: height 1.63, standoff 1.37, extent 7.621,7.239 7.873,8.001
3D body: height 1.5, standoff 0, extent 7.62,7.239 7.874,8.001
3D body: height 1.63, standoff 1.37, extent 5.842,7.239 7.747,8.001
3D body: height 1.63, standoff 1.37, extent 7.621,4.699 7.873,5.461
3D body: height 1.5, standoff 0, extent 7.62,4.699 7.874,5.461
3D body: height 1.63, standoff 1.37, extent 5.842,4.699 7.747,5.461
3D body: height 1.63, standoff 1.37, extent 7.621,14.859 7.873,15.621
3D body: height 1.5, standoff 0, extent 7.62,14.859 7.874,15.621
3D body: height 1.63, standoff 1.37, extent 5.842,14.859 7.747,15.621
3D body: height 1.63, standoff 1.37, extent 7.621,17.399 7.873,18.161
3D body: height 1.5, standoff 0, extent 7.62,17.399 7.874,18.161
3D body: height 1.63, standoff 1.37, extent 5.842,17.399 7.747,18.161
3D body: height 1.63, standoff 1.37, extent 7.621,19.939 7.873,20.701
3D body: height 1.5, standoff 0, extent 7.62,19.939 7.874,20.701
3D body: height 1.63, standoff 1.37, extent 5.842,19.939 7.747,20.701
3D body: height 1.63, standoff 1.37, extent 7.621,22.479 7.873,23.241
3D body: height 1.5, standoff 0, extent 7.62,22.479 7.874,23.241
3D body: height 1.63, standoff 1.37, extent 5.842,22.479 7.747,23.241
3D body: height 1.63, standoff 1.37, extent 7.621,25.019 7.873,25.781
3D body: height 1.5, standoff 0, extent 7.62,25.019 7.874,25.781
3D body: height 1.63, standoff 1.37, extent 5.842,25.019 7.747,25.781
3D body: height 1.63, standoff 1.37, extent 7.621,27.559 7.873,28.321
3D body: height 1.5, standoff 0, extent 7.62,27.559 7.874,28.321
3D body: height 1.63, standoff 1.37, extent 5.842,27.559 7.747,28.321
3D body: height 1.63, standoff 1.37, extent 7.621,30.099 7.873,30.861
3D body: height 1.5, standoff 0, extent 7.62,30.099 7.874,30.861
3D body: height 1.63, standoff 1.37, extent 5.842,30.099 7.747,30.861
3D body: height 1.63, standoff 1.37, extent 7.621,32.639 7.873,33.401
3D body: height 1.5, standoff 0, extent 7.62,32.639 7.874,33.401
3D body: height 1.63, standoff 1.37, extent 5.842,32.639 7.747,33.401
3D body: height 1.63, standoff 1.37, extent -0.127,2.159 1.778,2.921
3D body: height 1.5, standoff 0, extent -0.254,2.159 0,2.921
3D body: height 1.63, standoff 1.37, extent -0.253,2.159 -0.001,2.921
3D body: height 1.63, standoff 1.37, extent -0.127,30.099 1.778,30.861
3D body: height 1.63, standoff 1.37, extent -0.127,32.639 1.778,33.401
3D body: height 1.63, standoff 1.37, extent -0.127,27.559 1.778,28.321
3D body: height 1.63, standoff 1.37, extent -0.127,25.019 1.778,25.781
3D body: height 1.63, standoff 1.37, extent -0.127,22.479 1.778,23.241
3D body: height 1.63, standoff 1.37, extent -0.127,19.939 1.778,20.701
3D body: height 1.63, standoff 1.37, extent -0.127,17.399 1.778,18.161
3D body: height 1.63, standoff 1.37, extent -0.127,14.859 1.778,15.621
3D body: height 1.63, standoff 1.37, extent -0.127,12.319 1.778,13.081
3D body: height 1.63, standoff 1.37, extent -0.127,9.779 1.778,10.541
3D body: height 1.63, standoff 1.37, extent -0.127,7.239 1.778,8.001
3D body: height 1.63, standoff 1.37, extent -0.127,4.699 1.778,5.461
3D body: height 1.63, standoff 1.37, extent -0.126,32.639 0.126,33.401
3D body: height 1.5, standoff 0, extent -0.127,32.639 0.127,33.401
3D body: height 1.63, standoff 1.37, extent -0.126,30.099 0.126,30.861
3D body: height 1.5, standoff 0, extent -0.127,30.099 0.127,30.861
3D body: height 1.63, standoff 1.37, extent -0.126,27.559 0.126,28.321
3D body: height 1.5, standoff 0, extent -0.127,27.559 0.127,28.321
3D body: height 1.63, standoff 1.37, extent -0.126,25.019 0.126,25.781
3D body: height 1.5, standoff 0, extent -0.127,25.019 0.127,25.781
3D body: height 1.63, standoff 1.37, extent -0.126,22.479 0.126,23.241
3D body: height 1.5, standoff 0, extent -0.127,22.479 0.127,23.241
3D body: height 1.63, standoff 1.37, extent -0.126,19.939 0.126,20.701
3D body: height 1.5, standoff 0, extent -0.127,19.939 0.127,20.701
3D body: height 1.63, standoff 1.37, extent -0.126,17.399 0.126,18.161
3D body: height 1.5, standoff 0, extent -0.127,17.399 0.127,18.161
3D body: height 1.63, standoff 1.37, extent -0.126,14.859 0.126,15.621
3D body: height 1.5, standoff 0, extent -0.127,14.859 0.127,15.621
3D body: height 1.63, standoff 1.37, extent -0.126,12.192 0.126,12.954
3D body: height 1.5, standoff 0, extent -0.127,12.192 0.127,12.954
3D body: height 1.63, standoff 1.37, extent -0.126,9.779 0.126,10.541
3D body: height 1.5, standoff 0, extent -0.127,9.779 0.127,10.541
3D body: height 1.63, standoff 1.37, extent -0.126,7.239 0.126,8.001
3D body: height 1.5, standoff 0, extent -0.127,7.239 0.127,8.001
3D body: height 1.63, standoff 1.37, extent -0.126,4.699 0.126,5.461
3D body: height 1.5, standoff 0, extent -0.127,4.699 0.127,5.461
3D body: height 2, standoff 1.1, extent 1.27,-1.27 6.35,34.29
3D body: height 1.63, standoff 1.37, extent -0.381,-0.381 -0.128,0.381
3D body: height 1.5, standoff 0, extent -0.381,-0.381 -0.127,0.381
3D body: height 1.63, standoff 1.37, extent -0.126,-0.381 1.779,0.381
3D body: height 1.63, standoff 1.37, extent 7.494,2.159 7.746,2.921
3D body: height 1.5, standoff 0, extent 7.493,2.159 7.747,2.921
3D body: height 2.51, standoff 2.5, extent 2.041,32.532 3.039,33.528
3D body: height 2.5, standoff 2, extent 1.778,-1.27 5.842,34.29

## LCD-16x2 [mm]
pads (20):
  oval 1.524x2 hole 1: 0(0,0) 1(2.54,0) 2(5.08,0) 3(7.62,0) 4(10.16,0) 5(12.7,0) 6(15.24,0) 7(17.78,0) 8(20.32,0) 9(22.86,0) 10(25.4,0) 11(27.94,0) 12(30.48,0) 13(33.02,0) 14(35.56,0) 15(38.1,0)
  round 1.524 hole 2.5: no(-6,-31.85) no(-6,0.15) no(69,-31.85) no(69,0.15)
Top Overlay:
  lines w0.254: -8.509,-34.35 -8.509,2.032 -8.5,2.041 -8.5,2.65 71.5,2.65 71.5,-34.35 -8.5,-34.35 ; 71.5,1.652 71.501,1.651
3D body: height 11.5, standoff 11, extent -7.45,-1.4 -4.456,1.588
3D body: height 11.5, standoff 11, extent -7.425,-33.275 -4.431,-30.287
3D body: height 11.5, standoff 11, extent 67.425,-33.325 70.419,-30.337
3D body: height 11.5, standoff 11, extent 67.725,-1.2 70.719,1.788
3D body: height 14.4, standoff 11, extent 66.675,-25.4 71.12,-7.62
3D body: height 21.6, standoff 20.6, extent -1.27,-22.86 64.135,-8.89
3D body: height 20.6, standoff 10.6, extent -3.81,-27.94 66.675,-4.445
3D body: height 9.6, standoff 0, extent 37.592,-0.508 38.59,0.488
3D body: height 9.6, standoff 0, extent 35.052,-0.508 36.05,0.488
3D body: height 9.6, standoff 0, extent 32.512,-0.508 33.51,0.488
3D body: height 9.6, standoff 0, extent 29.972,-0.508 30.97,0.488
3D body: height 9.6, standoff 0, extent 27.432,-0.508 28.43,0.488
3D body: height 9.6, standoff 0, extent 24.892,-0.508 25.89,0.488
3D body: height 9.6, standoff 0, extent 22.352,-0.508 23.35,0.488
3D body: height 9.6, standoff 0, extent 19.812,-0.508 20.81,0.488
3D body: height 9.6, standoff 0, extent 17.272,-0.508 18.27,0.488
3D body: height 9.6, standoff 0, extent 14.732,-0.508 15.73,0.488
3D body: height 9.6, standoff 0, extent 12.192,-0.508 13.19,0.488
3D body: height 9.6, standoff 0, extent 9.652,-0.508 10.65,0.488
3D body: height 9.6, standoff 0, extent 7.112,-0.508 8.11,0.488
3D body: height 9.6, standoff 0, extent 4.572,-0.508 5.57,0.488
3D body: height 9.6, standoff 0, extent 2.032,-0.508 3.03,0.488
3D body: height 9.6, standoff 0, extent -0.508,-0.508 0.49,0.488
3D body: height 11, standoff 9.4, extent -8.382,-34.036 71.374,2.667

## LCD_20_4 [mm]
pads (36):
  oct 1.8x1.8 hole 1.7: 0(-46.712,27.5) 0(-46.672,-27.5) 0(46.712,-27.5) 0(46.712,27.5)
  oct 1.7x1.7 hole 0.9: 1(-39.052,-27.46) 1(-39.052,27.46) 2(-36.512,-27.46) 2(-36.512,27.46) 3(-33.972,-27.46) 3(-33.972,27.46) 4(-31.432,-27.46) 4(-31.432,27.46) 5(-28.892,-27.46) 5(-28.892,27.46) 6(-26.352,-27.46) 6(-26.352,27.46) 7(-23.812,-27.46) 7(-23.812,27.46) 8(-21.273,-27.46) 8(-21.273,27.46) 9(-18.732,-27.46) 9(-18.732,27.46) 10(-16.192,-27.46) 10(-16.192,27.46) 11(-13.652,-27.46) 11(-13.652,27.46) 12(-11.112,-27.46) 12(-11.112,27.46) 13(-8.572,-27.46) 13(-8.572,27.46) 14(-6.032,-27.46) 14(-6.032,27.46) 15(-3.492,-27.46) 15(-3.492,27.46) 16(-0.953,-27.46) 16(-0.953,27.46)
Top Overlay:
  lines w0.254: -49.212,-30 -49.212,30 49.212,30 49.212,-30 -49.212,-30
3D body: height 12.5, standoff 12, extent -47.752,26.035 -44.764,29.029
3D body: height 12.5, standoff 12, extent 45.085,25.908 48.073,28.902
3D body: height 12.5, standoff 12, extent 45.339,-28.702 48.327,-25.708
3D body: height 12.5, standoff 12, extent -48.006,-28.956 -45.018,-25.962
3D body: height 21, standoff 20.5, extent -36.195,-11.43 36.83,11.43
3D body: height 20.5, standoff 12, extent -46.99,-19.177 47.117,19.685
3D body: height 12, standoff 10.5, extent -49.276,-30.226 49.911,29.972
3D body: height 12, standoff 10.5
3D body: height 10.8, standoff 0, extent -1.397,-27.94 -0.401,-26.942
3D body: height 10.8, standoff 0, extent -3.937,-27.94 -2.941,-26.942
3D body: height 10.8, standoff 0, extent -6.477,-27.94 -5.481,-26.942
3D body: height 10.8, standoff 0, extent -9.017,-27.94 -8.021,-26.942
3D body: height 10.8, standoff 0, extent -11.557,-27.94 -10.561,-26.942
3D body: height 10.8, standoff 0, extent -14.097,-27.94 -13.101,-26.942
3D body: height 10.8, standoff 0, extent -16.637,-27.94 -15.641,-26.942
3D body: height 10.8, standoff 0, extent -19.177,-27.94 -18.181,-26.942
3D body: height 10.8, standoff 0, extent -21.717,-27.94 -20.721,-26.942
3D body: height 10.8, standoff 0, extent -24.257,-27.94 -23.261,-26.942
3D body: height 10.8, standoff 0, extent -26.924,-27.94 -25.928,-26.942
3D body: height 10.8, standoff 0, extent -29.337,-27.94 -28.341,-26.942
3D body: height 10.8, standoff 0, extent -31.877,-27.94 -30.881,-26.942
3D body: height 10.8, standoff 0, extent -34.417,-27.94 -33.421,-26.942
3D body: height 10.8, standoff 0, extent -36.957,-27.94 -35.961,-26.942
3D body: height 10.8, standoff 0, extent -39.497,-27.94 -38.501,-26.942
3D body: height 10.8, standoff 0, extent -1.397,27.051 -0.401,28.049
3D body: height 10.8, standoff 0, extent -3.937,27.051 -2.941,28.049
3D body: height 10.8, standoff 0, extent -6.477,27.051 -5.481,28.049
3D body: height 10.8, standoff 0, extent -9.017,26.924 -8.021,27.922
3D body: height 10.8, standoff 0, extent -11.557,27.051 -10.561,28.049
3D body: height 10.8, standoff 0, extent -14.097,27.051 -13.101,28.049
3D body: height 10.8, standoff 0, extent -16.637,27.051 -15.641,28.049
3D body: height 10.8, standoff 0, extent -19.177,26.924 -18.181,27.922
3D body: height 10.8, standoff 0, extent -21.717,27.051 -20.721,28.049
3D body: height 10.8, standoff 0, extent -24.257,27.051 -23.261,28.049
3D body: height 10.8, standoff 0, extent -26.924,26.924 -25.928,27.922
3D body: height 10.8, standoff 0, extent -29.337,27.051 -28.341,28.049
3D body: height 10.8, standoff 0, extent -32.004,27.051 -31.008,28.049
3D body: height 10.8, standoff 0, extent -34.544,26.924 -33.548,27.922
3D body: height 10.8, standoff 0, extent -36.957,27.051 -35.961,28.049
3D body: height 10.8, standoff 0, extent -39.624,26.924 -38.628,27.922

## LED-BLUE [mm]
pads (2):
  oct 1.7x1.7 hole 1: 1(-1.27,0) 2(1.27,0)
Top Overlay:
  lines w0.254: -2.74,-1.257 -2.74,1.176 cw(c-0.127,0) -2.663,-1.334
3D body: height 6.5, standoff 1, extent -2.617,-2.413 2.363,2.577
3D body: height 9, standoff 4, extent -2.614,-2.402 2.36,2.577
3D body: height 1, standoff 0, extent -2.911,-2.667 2.667,2.921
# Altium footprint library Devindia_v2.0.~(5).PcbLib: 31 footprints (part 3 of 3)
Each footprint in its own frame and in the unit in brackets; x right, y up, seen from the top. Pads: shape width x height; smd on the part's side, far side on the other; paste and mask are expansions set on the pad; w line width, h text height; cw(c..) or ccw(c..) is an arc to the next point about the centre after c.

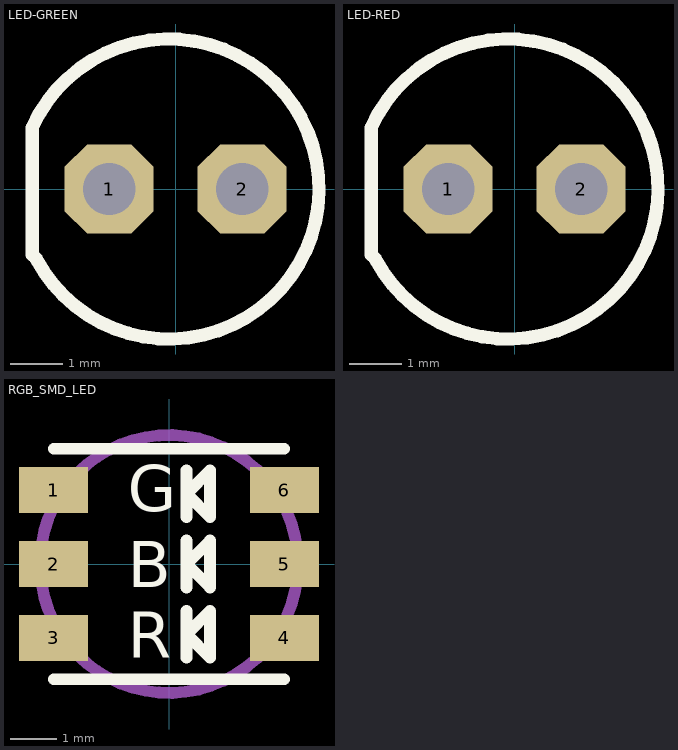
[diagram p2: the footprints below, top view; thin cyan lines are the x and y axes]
## LED-GREEN [mm]
pads (2):
  oct 1.7x1.7 hole 1: 1(-1.27,0) 2(1.27,0)
Top Overlay:
  lines w0.254: -2.74,-1.257 -2.74,1.176 cw(c-0.127,0) -2.663,-1.334
3D body: height 6.5, standoff 1, extent -2.617,-2.413 2.363,2.577
3D body: height 9, standoff 4, extent -2.614,-2.402 2.36,2.577
3D body: height 1, standoff 0, extent -2.911,-2.667 2.667,2.921

## LED-RED [mm]
pads (2):
  oct 1.7x1.7 hole 1: 1(-1.27,0) 2(1.27,0)
Top Overlay:
  lines w0.254: -2.74,-1.257 -2.74,1.176 cw(c-0.127,0) -2.663,-1.334
3D body: height 1, standoff 0, extent -2.911,-2.667 2.667,2.921
3D body: height 9, standoff 4, extent -2.614,-2.402 2.36,2.577
3D body: height 6.5, standoff 1, extent -2.617,-2.413 2.363,2.577

## RGB_SMD_LED [mm]
pads (6):
  rect 1.5x1 all layers, no hole: 1(-2.5,1.6) 2(-2.5,0) 3(-2.5,-1.6) 4(2.5,-1.6) 5(2.5,0) 6(2.5,1.6)
Top Overlay:
  lines w0.254: -2.5,-2.5 2.5,-2.5 ; -2.5,2.5 2.5,2.5 ; 0.381,-2.032 0.381,-1.016 0.381,-1.524 ; 0.381,-0.508 0.381,0.508 0.381,0 ; 0.381,1.016 0.381,2.032 0.381,1.524 ; 0.381,-1.524 0.889,-2.032 0.889,-1.016 0.381,-1.524 ; 0.381,0 0.889,-0.508 0.889,0.508 0.381,0 ; 0.381,1.524 0.889,1.016 0.889,2.032 0.381,1.524
  text "R" at -0.889,-2.032 h1
  text "B" at -0.889,-0.508 h1
  text "G" at -0.889,1.143 h1
Mechanical 1:
  circle w0.254: c0,0 r2.794
3D body: height 1.7, standoff 1.68, extent -2.286,-2.794 -0.254,-1.27
3D body: height 1.7, standoff 1.68, extent -0.889,-0.889 2.667,0.889
3D body: height 1.7, standoff 1.68, extent -2.794,-0.381 -1.524,0.381
3D body: height 0.2, standoff 0, extent 1.825,1.27 3.095,1.905
3D body: height 0.2, standoff 0, extent 1.825,-0.33 3.095,0.305
3D body: height 0.2, standoff 0, extent 1.825,-1.93 3.095,-1.295
3D body: height 0.2, standoff 0, extent -3.175,-1.93 -1.905,-1.295
3D body: height 0.2, standoff 0, extent -3.175,-0.33 -1.905,0.305
3D body: height 0.2, standoff 0, extent -3.175,1.27 -1.905,1.905
3D body: height 1.68, standoff 0.2, extent -3.429,-3.175 3.429,3.175
3D body: height 1.7, standoff 1.68, extent -2.286,1.27 -0.254,2.794
3D body: height 1.7, standoff 1.68, extent 0.254,0.762 2.159,2.794
3D body: height 1.7, standoff 1.68, extent 0.381,-2.794 2.159,-0.762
